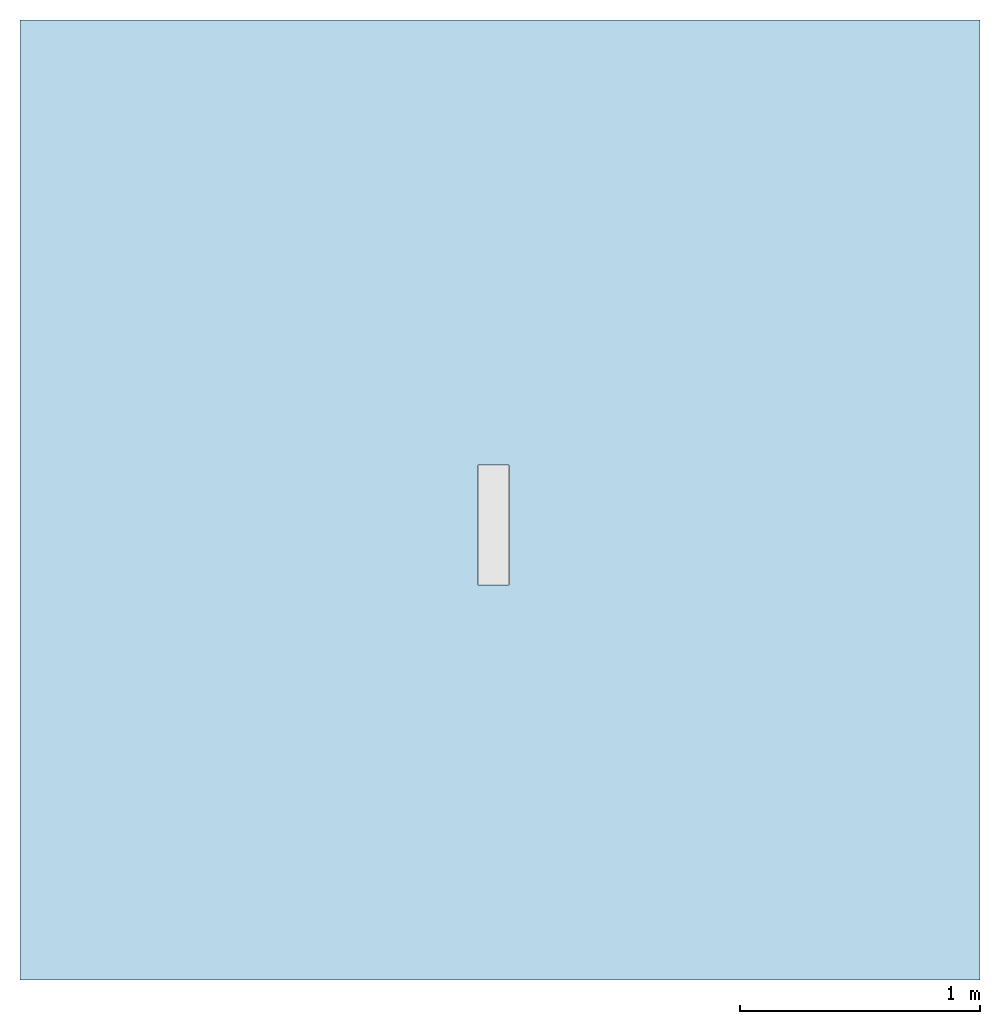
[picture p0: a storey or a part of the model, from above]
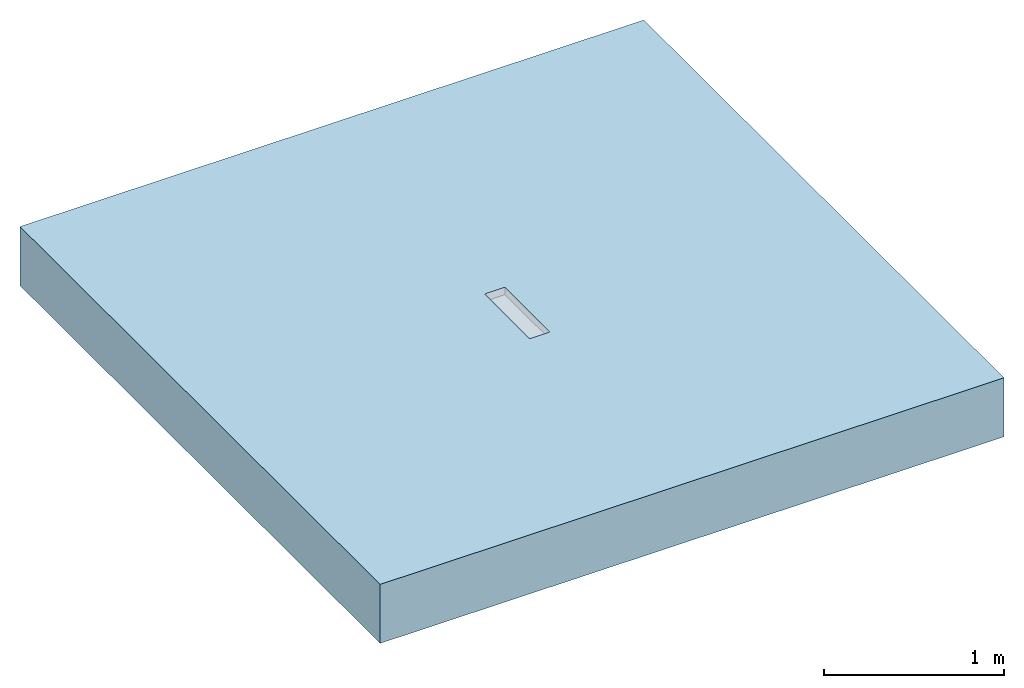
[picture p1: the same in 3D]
Properties of the parts of a building model (IFC2X3)

# File
Description: ViewDefinition [CoordinationView]
File name: Project Number
Time: 2014-06-06T15:09:35
Written by: The EXPRESS Data Manager Version 5.01.0100.02.64mod : 6 Jun 2012
Made in: 20130308_1515(x64) - Exporter 2014.0.2013.0308 - Default UI
Comment: STEP Physical File produced by: The EXPRESS Data Manager Version 5.01.0100.02.64mod : 6 Jun 2012 * Module: EDMstepFileFactory/EDMstandAlone * Creation date: Fri Jun 06 15:09:35 2014 * Host: IN-BLR-PC-0010 * Database: C:\Users\palleri\AppData\Local\Temp\{5C33276D-9CA4-45E0-9B33-8EF15D7D8712}\ifc * Database version: 5507 * Database creation date: Fri Jun 06 15:09:34 2014 * Schema: IFC2X3 * Model: DataRepository.ifc * Model creation date: Fri Jun 06 15:09:35 2014 * Header model: DataRepository.ifc_HeaderModel * Header model creation date: Fri Jun 06 15:09:35 2014 * EDMuser: sdai-user * EDMgroup: sdai-group * License ID and type: 5605 : Permanent license. Expiry date: * EDMstepFileFactory options: 020000

# IfcProject, Project Number
LongName: Project Name; Phase: Project Status

# IfcSite, Default
RefLatitude: 42, 21, 30, 344238; RefLongitude: -71, -3, -35, -194702; RefElevation: 0 mm

# IfcBuilding
Pset_BuildingCommon - NumberOfStoreys: 1
Other - Project Status: Project Status; Project Issue Date: Issue Date; Project Name: Project Name; Project Address: ## Street City, State Zip; Client Name: Owner; Project Number: Project Number

# IfcBuildingStorey, Level 1
LongName: Level 1; Elevation: 0 mm
Graphics - Line Weight: 1; Symbol: M_Level Head - Circle: M_Level Head - Circle; Color: 0; Symbol at End 2 Default: yes; Line Pattern: Center; Symbol at End 1 Default: no
Constraints - Elevation Base: Project Base Point; Elevation: 0 mm
Identity Data - Building Story: yes; Name: Level 1; Structural: no
Dimensions - Computation Height: 0 mm

# IfcFlowTerminal: 38147 - Fixed Height Channel - Shallow Section - 500mm LG - Invert Depth 50mm, ACO Freedeck Fixed Height Channel Shallow Section - Galvanized Steel:38147 - Fixed Height Channel - Shallow Section - 500mm LG - Invert Depth 50mm:308688
In: Level 1
Material: Galvanized Steel
Construction - 36955 - Grating - Plain Mesh - Stainless Steel 304 - 1000mm long: no; 36953 - Grating - Plain Mesh - Galvanised Steel - 1000mm long: yes; 36952 - Grating - Plain Mesh - Galvanised Steel - 500mm long: no; End Plate Invert 2: no; End Plate Invert 1: no; 36954 - Grating - Plain Mesh - Stainless Steel 304 - 500mm long: no; 00276 - Grating - Slotted Grating - Galvanised Steel - 1000mm long: no; 00273 - Grating - Slotted Grating - Stainless Steel 304 - 500mm long: no; 00277 - Grating - Slotted Grating - Galvanised Steel - 500mm long: no; 00272 - Grating - Slotted Grating - Stainless Steel 304 - 1000mm long: no
Constraints - Moves With Nearby Elements: no; Level: Level: Level 1
Identity Data - Mark: 28; E-mail Sales: abdcommercial@aco.co.uk; Manufacturer: ACO Building Drainage; Watermarked With: BIM Manager Premium Suite; Telephone: +44 (0)1462 816666; Address: ACO Business Centre, Caxton Road, Bedford, MK41 0LF; E-mail Technical: abdtechnical@aco.co.uk; Fax: +44 (0)1462 851490; Watermarked By: www.acobd.com; Website: www.acobd.com; Watermark1: This file is the property of ACO Technologies PLC; Watermark2: This file is water marked and users are prohibited to reproduce, adapt, distribute this information
Phasing - Phase Created: New Construction
Pset_ManufacturerTypeInformation - Manufacturer: ACO Building Drainage
Materials and Finishes - Material: Galvanized Steel
General - Weight (Kg): 1.1kg; Channel Material: Hot Dipped Galvanised Steel; Installation Guidelines: X:\Electronic Literature\ABD Electronic Literature\Roof and Balcony Drainage\ACO Freedeck Brochure.pdf; Channel Recyclable: Fully recyclable; Product Code: 38147; Product Type: Linear Deck Drainage System; Price: POA - contact ACO; Product Standard: BS EN 1433:2002, CE marked; Dimensions (LxWxH): 500 x 130 x 50; Product Range: ACO Freedeck; Channel Recycled Material Content: 25 - 30 %; Maintenance Guidelines: X:\Electronic Literature\ABD Electronic Literature\Roof and Balcony Drainage\ACO Freedeck Brochure.pdf; NBS Specification: NBS Section R10 Gravity Rainwater Drainage Systems, Subsection 365; Load Class: A15; Product Description: ACO FreeDeck Fixed Height Channel - Shallow Section; Channel Colour: Galvanised
Dimensions - Channel End Length: -500 mm; Height: 50 mm; Grating End Length: 500 mm
Model Properties - Grating Product Code 36952: Load Class A15 - Mesh Grating - 14mm x 30mm Mesh - Galvanized Steel - 500mm long - 1.6kg; Grating Product Code 00277: Load Class A15 - Slotted Grating - 10 x 80mm Slot - Galvanized Steel - 500mm long - 1.0kg; End Plate Product Code 38148: End Plate - Galvanized Steel for Invert Depth - 50mm - 0.1Kg; Grating Product Code 00276: Load Class A15 - Slotted Grating - 10 x 80mm Slot - Galvanized Steel - 1000mm long - 2.2kg; Grating Product Code 36953: Load Class A15 - Mesh Grating - 14mm x 30mm Mesh - Galvanized Steel - 1000mm long - 3.0kg
Other - Nos: 16

# IfcSlab: Floor:Generic Floor - 400mm, Floor:Generic Floor - 400mm:193825
In: Level 1
PredefinedType: FLOOR; Material: Concrete, Broom Finish 400 mm
Structural - Enable Analytical Model: no; Structural: no
Dimensions - Thickness: 400 mm; Perimeter: 16000 mm; Volume: 6.39675 m3; Area: 16 m2
Constraints - Level: Level: Level 1; Room Bounding: yes; Height Offset From Level: 0 mm; Related to Mass: no
Phasing - Phase Created: New Construction
Pset_SlabCommon - Reference: Generic Floor - 400mm; IsExternal: no; LoadBearing: yes; ThermalTransmittance: 2.615 kg/K/s3; PitchAngle: 0 deg
Analytical Properties - Thermal mass: 604440; Absorptance: 0.1; Heat Transfer Coefficient (U): 2.615; Thermal Resistance (R): 0.382409; Roughness: 1
Materials and Finishes - Structural Material: Concrete, Broom Finish
Construction - Function: Interior; Default Thickness: 400 mm
Graphics - Coarse Scale Fill Color: 0
